VERSION 5.7 ;
  NOWIREEXTENSIONATPIN ON ;
  DIVIDERCHAR "/" ;
  BUSBITCHARS "[]" ;
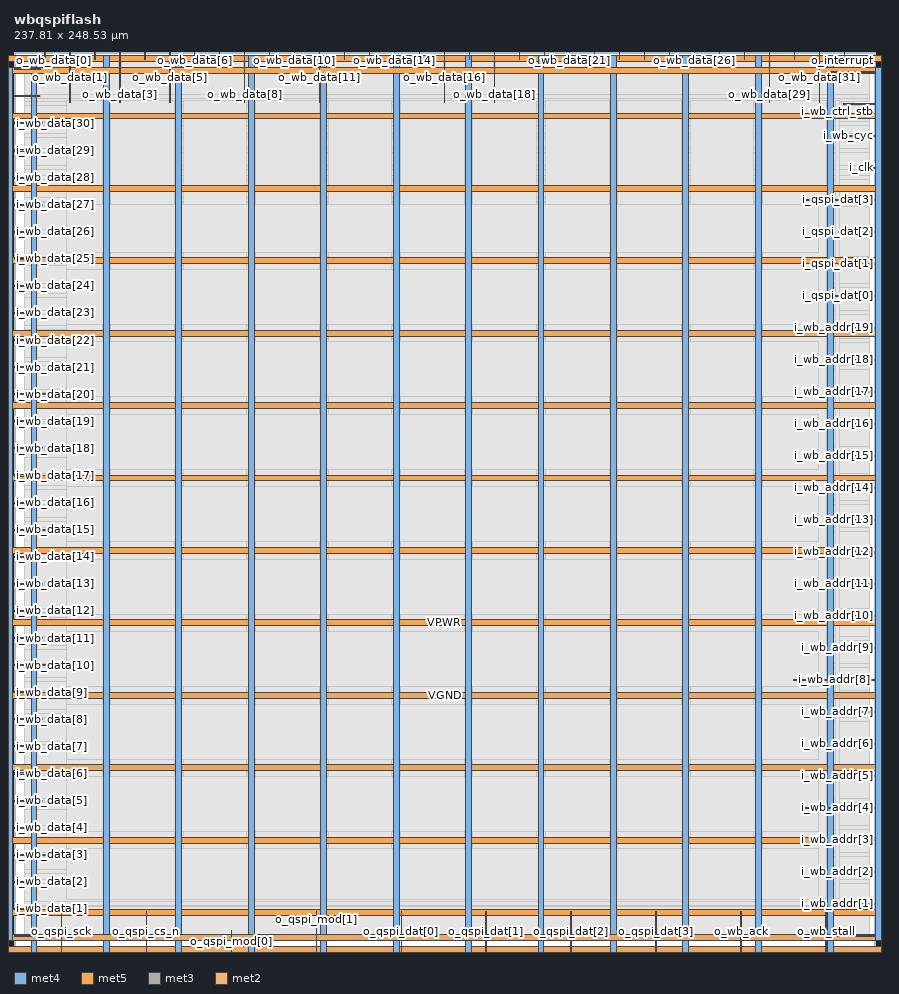
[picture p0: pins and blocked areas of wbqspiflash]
MACRO wbqspiflash
  CLASS BLOCK ;
  FOREIGN wbqspiflash ;
  ORIGIN 0.000 0.000 ;
  SIZE 237.810 BY 248.530 ;
  PIN VGND
    DIRECTION INOUT ;
    USE GROUND ;
    PORT
      LAYER met4 ;
        RECT -5.380 -0.020 -3.780 247.540 ;
    END
    PORT
      LAYER met5 ;
        RECT -5.380 -0.020 242.740 1.580 ;
    END
    PORT
      LAYER met5 ;
        RECT -5.380 245.940 242.740 247.540 ;
    END
    PORT
      LAYER met4 ;
        RECT 241.140 -0.020 242.740 247.540 ;
    END
    PORT
      LAYER met4 ;
        RECT 24.720 -0.020 26.320 247.540 ;
    END
    PORT
      LAYER met4 ;
        RECT 64.720 -0.020 66.320 247.540 ;
    END
    PORT
      LAYER met4 ;
        RECT 104.720 -0.020 106.320 247.540 ;
    END
    PORT
      LAYER met4 ;
        RECT 144.720 -0.020 146.320 247.540 ;
    END
    PORT
      LAYER met4 ;
        RECT 184.720 -0.020 186.320 247.540 ;
    END
    PORT
      LAYER met4 ;
        RECT 224.720 -0.020 226.320 247.540 ;
    END
    PORT
      LAYER met5 ;
        RECT -5.380 30.080 242.740 31.680 ;
    END
    PORT
      LAYER met5 ;
        RECT -5.380 70.080 242.740 71.680 ;
    END
    PORT
      LAYER met5 ;
        RECT -5.380 110.080 242.740 111.680 ;
    END
    PORT
      LAYER met5 ;
        RECT -5.380 150.080 242.740 151.680 ;
    END
    PORT
      LAYER met5 ;
        RECT -5.380 190.080 242.740 191.680 ;
    END
    PORT
      LAYER met5 ;
        RECT -5.380 230.080 242.740 231.680 ;
    END
  END VGND
  PIN VPWR
    DIRECTION INOUT ;
    USE POWER ;
    PORT
      LAYER met4 ;
        RECT -2.080 3.280 -0.480 244.240 ;
    END
    PORT
      LAYER met5 ;
        RECT -2.080 3.280 239.440 4.880 ;
    END
    PORT
      LAYER met5 ;
        RECT -2.080 242.640 239.440 244.240 ;
    END
    PORT
      LAYER met4 ;
        RECT 237.840 3.280 239.440 244.240 ;
    END
    PORT
      LAYER met4 ;
        RECT 4.720 -0.020 6.320 247.540 ;
    END
    PORT
      LAYER met4 ;
        RECT 44.720 -0.020 46.320 247.540 ;
    END
    PORT
      LAYER met4 ;
        RECT 84.720 -0.020 86.320 247.540 ;
    END
    PORT
      LAYER met4 ;
        RECT 124.720 -0.020 126.320 247.540 ;
    END
    PORT
      LAYER met4 ;
        RECT 164.720 -0.020 166.320 247.540 ;
    END
    PORT
      LAYER met4 ;
        RECT 204.720 -0.020 206.320 247.540 ;
    END
    PORT
      LAYER met5 ;
        RECT -5.380 10.080 242.740 11.680 ;
    END
    PORT
      LAYER met5 ;
        RECT -5.380 50.080 242.740 51.680 ;
    END
    PORT
      LAYER met5 ;
        RECT -5.380 90.080 242.740 91.680 ;
    END
    PORT
      LAYER met5 ;
        RECT -5.380 130.080 242.740 131.680 ;
    END
    PORT
      LAYER met5 ;
        RECT -5.380 170.080 242.740 171.680 ;
    END
    PORT
      LAYER met5 ;
        RECT -5.380 210.080 242.740 211.680 ;
    END
  END VPWR
  PIN i_clk
    DIRECTION INPUT ;
    USE SIGNAL ;
    PORT
      LAYER met3 ;
        RECT 234.910 216.430 237.810 216.730 ;
    END
  END i_clk
  PIN i_qspi_dat[0]
    DIRECTION INPUT ;
    USE SIGNAL ;
    PORT
      LAYER met3 ;
        RECT 224.390 181.070 237.810 181.370 ;
    END
  END i_qspi_dat[0]
  PIN i_qspi_dat[1]
    DIRECTION INPUT ;
    USE SIGNAL ;
    PORT
      LAYER met3 ;
        RECT 227.545 189.910 237.810 190.210 ;
    END
  END i_qspi_dat[1]
  PIN i_qspi_dat[2]
    DIRECTION INPUT ;
    USE SIGNAL ;
    PORT
      LAYER met3 ;
        RECT 227.545 198.750 237.810 199.050 ;
    END
  END i_qspi_dat[2]
  PIN i_qspi_dat[3]
    DIRECTION INPUT ;
    USE SIGNAL ;
    PORT
      LAYER met3 ;
        RECT 218.410 207.590 237.810 207.890 ;
    END
  END i_qspi_dat[3]
  PIN i_wb_addr[0]
    DIRECTION INPUT ;
    USE SIGNAL ;
    PORT
      LAYER met3 ;
        RECT 227.150 4.270 237.810 4.570 ;
    END
  END i_wb_addr[0]
  PIN i_wb_addr[10]
    DIRECTION INPUT ;
    USE SIGNAL ;
    PORT
      LAYER met3 ;
        RECT 224.390 92.670 237.810 92.970 ;
    END
  END i_wb_addr[10]
  PIN i_wb_addr[11]
    DIRECTION INPUT ;
    USE SIGNAL ;
    PORT
      LAYER met3 ;
        RECT 227.610 101.510 237.810 101.810 ;
    END
  END i_wb_addr[11]
  PIN i_wb_addr[12]
    DIRECTION INPUT ;
    USE SIGNAL ;
    PORT
      LAYER met3 ;
        RECT 227.150 110.350 237.810 110.650 ;
    END
  END i_wb_addr[12]
  PIN i_wb_addr[13]
    DIRECTION INPUT ;
    USE SIGNAL ;
    PORT
      LAYER met3 ;
        RECT 227.610 119.190 237.810 119.490 ;
    END
  END i_wb_addr[13]
  PIN i_wb_addr[14]
    DIRECTION INPUT ;
    USE SIGNAL ;
    PORT
      LAYER met3 ;
        RECT 227.610 128.030 237.810 128.330 ;
    END
  END i_wb_addr[14]
  PIN i_wb_addr[15]
    DIRECTION INPUT ;
    USE SIGNAL ;
    PORT
      LAYER met3 ;
        RECT 227.610 136.870 237.810 137.170 ;
    END
  END i_wb_addr[15]
  PIN i_wb_addr[16]
    DIRECTION INPUT ;
    USE SIGNAL ;
    PORT
      LAYER met3 ;
        RECT 224.390 145.710 237.810 146.010 ;
    END
  END i_wb_addr[16]
  PIN i_wb_addr[17]
    DIRECTION INPUT ;
    USE SIGNAL ;
    PORT
      LAYER met3 ;
        RECT 227.150 154.550 237.810 154.850 ;
    END
  END i_wb_addr[17]
  PIN i_wb_addr[18]
    DIRECTION INPUT ;
    USE SIGNAL ;
    PORT
      LAYER met3 ;
        RECT 227.610 163.390 237.810 163.690 ;
    END
  END i_wb_addr[18]
  PIN i_wb_addr[19]
    DIRECTION INPUT ;
    USE SIGNAL ;
    PORT
      LAYER met3 ;
        RECT 227.150 172.230 237.810 172.530 ;
    END
  END i_wb_addr[19]
  PIN i_wb_addr[1]
    DIRECTION INPUT ;
    USE SIGNAL ;
    PORT
      LAYER met3 ;
        RECT 231.750 13.110 237.810 13.410 ;
    END
  END i_wb_addr[1]
  PIN i_wb_addr[2]
    DIRECTION INPUT ;
    USE SIGNAL ;
    PORT
      LAYER met3 ;
        RECT 227.610 21.950 237.810 22.250 ;
    END
  END i_wb_addr[2]
  PIN i_wb_addr[3]
    DIRECTION INPUT ;
    USE SIGNAL ;
    PORT
      LAYER met3 ;
        RECT 227.610 30.790 237.810 31.090 ;
    END
  END i_wb_addr[3]
  PIN i_wb_addr[4]
    DIRECTION INPUT ;
    USE SIGNAL ;
    PORT
      LAYER met3 ;
        RECT 217.950 39.630 237.810 39.930 ;
    END
  END i_wb_addr[4]
  PIN i_wb_addr[5]
    DIRECTION INPUT ;
    USE SIGNAL ;
    PORT
      LAYER met3 ;
        RECT 227.610 48.470 237.810 48.770 ;
    END
  END i_wb_addr[5]
  PIN i_wb_addr[6]
    DIRECTION INPUT ;
    USE SIGNAL ;
    PORT
      LAYER met3 ;
        RECT 228.530 57.310 237.810 57.610 ;
    END
  END i_wb_addr[6]
  PIN i_wb_addr[7]
    DIRECTION INPUT ;
    USE SIGNAL ;
    PORT
      LAYER met3 ;
        RECT 231.750 66.150 237.810 66.450 ;
    END
  END i_wb_addr[7]
  PIN i_wb_addr[8]
    DIRECTION INPUT ;
    USE SIGNAL ;
    PORT
      LAYER met3 ;
        RECT 215.190 74.990 237.810 75.290 ;
    END
  END i_wb_addr[8]
  PIN i_wb_addr[9]
    DIRECTION INPUT ;
    USE SIGNAL ;
    PORT
      LAYER met3 ;
        RECT 228.070 83.830 237.810 84.130 ;
    END
  END i_wb_addr[9]
  PIN i_wb_ctrl_stb
    DIRECTION INPUT ;
    USE SIGNAL ;
    PORT
      LAYER met3 ;
        RECT 228.990 234.110 237.810 234.410 ;
    END
  END i_wb_ctrl_stb
  PIN i_wb_cyc
    DIRECTION INPUT ;
    USE SIGNAL ;
    PORT
      LAYER met3 ;
        RECT 228.530 225.270 237.810 225.570 ;
    END
  END i_wb_cyc
  PIN i_wb_data[0]
    DIRECTION INPUT ;
    USE SIGNAL ;
    PORT
      LAYER met3 ;
        RECT 0.000 4.270 7.910 4.570 ;
    END
  END i_wb_data[0]
  PIN i_wb_data[10]
    DIRECTION INPUT ;
    USE SIGNAL ;
    PORT
      LAYER met3 ;
        RECT 0.000 79.070 15.730 79.370 ;
    END
  END i_wb_data[10]
  PIN i_wb_data[11]
    DIRECTION INPUT ;
    USE SIGNAL ;
    PORT
      LAYER met3 ;
        RECT 0.000 86.550 7.910 86.850 ;
    END
  END i_wb_data[11]
  PIN i_wb_data[12]
    DIRECTION INPUT ;
    USE SIGNAL ;
    PORT
      LAYER met3 ;
        RECT 0.000 94.030 4.230 94.330 ;
    END
  END i_wb_data[12]
  PIN i_wb_data[13]
    DIRECTION INPUT ;
    USE SIGNAL ;
    PORT
      LAYER met3 ;
        RECT 0.000 101.510 7.910 101.810 ;
    END
  END i_wb_data[13]
  PIN i_wb_data[14]
    DIRECTION INPUT ;
    USE SIGNAL ;
    PORT
      LAYER met3 ;
        RECT 0.000 108.990 4.230 109.290 ;
    END
  END i_wb_data[14]
  PIN i_wb_data[15]
    DIRECTION INPUT ;
    USE SIGNAL ;
    PORT
      LAYER met3 ;
        RECT 0.000 116.470 15.730 116.770 ;
    END
  END i_wb_data[15]
  PIN i_wb_data[16]
    DIRECTION INPUT ;
    USE SIGNAL ;
    PORT
      LAYER met3 ;
        RECT 0.000 123.950 3.770 124.250 ;
    END
  END i_wb_data[16]
  PIN i_wb_data[17]
    DIRECTION INPUT ;
    USE SIGNAL ;
    PORT
      LAYER met3 ;
        RECT 0.000 131.430 3.770 131.730 ;
    END
  END i_wb_data[17]
  PIN i_wb_data[18]
    DIRECTION INPUT ;
    USE SIGNAL ;
    PORT
      LAYER met3 ;
        RECT 0.000 138.910 7.910 139.210 ;
    END
  END i_wb_data[18]
  PIN i_wb_data[19]
    DIRECTION INPUT ;
    USE SIGNAL ;
    PORT
      LAYER met3 ;
        RECT 0.000 146.390 2.850 146.690 ;
    END
  END i_wb_data[19]
  PIN i_wb_data[1]
    DIRECTION INPUT ;
    USE SIGNAL ;
    PORT
      LAYER met3 ;
        RECT 0.000 11.750 3.770 12.050 ;
    END
  END i_wb_data[1]
  PIN i_wb_data[20]
    DIRECTION INPUT ;
    USE SIGNAL ;
    PORT
      LAYER met3 ;
        RECT 0.000 153.870 18.950 154.170 ;
    END
  END i_wb_data[20]
  PIN i_wb_data[21]
    DIRECTION INPUT ;
    USE SIGNAL ;
    PORT
      LAYER met3 ;
        RECT 0.000 161.350 4.230 161.650 ;
    END
  END i_wb_data[21]
  PIN i_wb_data[22]
    DIRECTION INPUT ;
    USE SIGNAL ;
    PORT
      LAYER met3 ;
        RECT 0.000 168.830 3.770 169.130 ;
    END
  END i_wb_data[22]
  PIN i_wb_data[23]
    DIRECTION INPUT ;
    USE SIGNAL ;
    PORT
      LAYER met3 ;
        RECT 0.000 176.310 4.230 176.610 ;
    END
  END i_wb_data[23]
  PIN i_wb_data[24]
    DIRECTION INPUT ;
    USE SIGNAL ;
    PORT
      LAYER met3 ;
        RECT 0.000 183.790 2.850 184.090 ;
    END
  END i_wb_data[24]
  PIN i_wb_data[25]
    DIRECTION INPUT ;
    USE SIGNAL ;
    PORT
      LAYER met3 ;
        RECT 0.000 191.270 4.230 191.570 ;
    END
  END i_wb_data[25]
  PIN i_wb_data[26]
    DIRECTION INPUT ;
    USE SIGNAL ;
    PORT
      LAYER met3 ;
        RECT 0.000 198.750 4.230 199.050 ;
    END
  END i_wb_data[26]
  PIN i_wb_data[27]
    DIRECTION INPUT ;
    USE SIGNAL ;
    PORT
      LAYER met3 ;
        RECT 0.000 206.230 7.910 206.530 ;
    END
  END i_wb_data[27]
  PIN i_wb_data[28]
    DIRECTION INPUT ;
    USE SIGNAL ;
    PORT
      LAYER met3 ;
        RECT 0.000 213.710 6.990 214.010 ;
    END
  END i_wb_data[28]
  PIN i_wb_data[29]
    DIRECTION INPUT ;
    USE SIGNAL ;
    PORT
      LAYER met3 ;
        RECT 0.000 221.190 3.770 221.490 ;
    END
  END i_wb_data[29]
  PIN i_wb_data[2]
    DIRECTION INPUT ;
    USE SIGNAL ;
    PORT
      LAYER met3 ;
        RECT 0.000 19.230 4.230 19.530 ;
    END
  END i_wb_data[2]
  PIN i_wb_data[30]
    DIRECTION INPUT ;
    USE SIGNAL ;
    PORT
      LAYER met3 ;
        RECT 0.000 228.670 7.910 228.970 ;
    END
  END i_wb_data[30]
  PIN i_wb_data[31]
    DIRECTION INPUT ;
    USE SIGNAL ;
    PORT
      LAYER met3 ;
        RECT 0.000 236.150 6.990 236.450 ;
    END
  END i_wb_data[31]
  PIN i_wb_data[3]
    DIRECTION INPUT ;
    USE SIGNAL ;
    PORT
      LAYER met3 ;
        RECT 0.000 26.710 11.130 27.010 ;
    END
  END i_wb_data[3]
  PIN i_wb_data[4]
    DIRECTION INPUT ;
    USE SIGNAL ;
    PORT
      LAYER met3 ;
        RECT 0.000 34.190 4.230 34.490 ;
    END
  END i_wb_data[4]
  PIN i_wb_data[5]
    DIRECTION INPUT ;
    USE SIGNAL ;
    PORT
      LAYER met3 ;
        RECT 0.000 41.670 7.910 41.970 ;
    END
  END i_wb_data[5]
  PIN i_wb_data[6]
    DIRECTION INPUT ;
    USE SIGNAL ;
    PORT
      LAYER met3 ;
        RECT 0.000 49.150 3.770 49.450 ;
    END
  END i_wb_data[6]
  PIN i_wb_data[7]
    DIRECTION INPUT ;
    USE SIGNAL ;
    PORT
      LAYER met3 ;
        RECT 0.000 56.630 4.230 56.930 ;
    END
  END i_wb_data[7]
  PIN i_wb_data[8]
    DIRECTION INPUT ;
    USE SIGNAL ;
    PORT
      LAYER met3 ;
        RECT 0.000 64.110 7.910 64.410 ;
    END
  END i_wb_data[8]
  PIN i_wb_data[9]
    DIRECTION INPUT ;
    USE SIGNAL ;
    PORT
      LAYER met3 ;
        RECT 0.000 71.590 3.770 71.890 ;
    END
  END i_wb_data[9]
  PIN i_wb_data_stb
    DIRECTION INPUT ;
    USE SIGNAL ;
    PORT
      LAYER met3 ;
        RECT 0.000 243.630 7.450 243.930 ;
    END
  END i_wb_data_stb
  PIN i_wb_we
    DIRECTION INPUT ;
    USE SIGNAL ;
    PORT
      LAYER met3 ;
        RECT 224.390 242.950 237.810 243.250 ;
    END
  END i_wb_we
  PIN o_interrupt
    DIRECTION OUTPUT TRISTATE ;
    USE SIGNAL ;
    PORT
      LAYER met2 ;
        RECT 229.240 246.530 229.380 248.530 ;
    END
  END o_interrupt
  PIN o_qspi_cs_n
    DIRECTION OUTPUT TRISTATE ;
    USE SIGNAL ;
    PORT
      LAYER met2 ;
        RECT 36.500 0.000 36.640 11.260 ;
    END
  END o_qspi_cs_n
  PIN o_qspi_dat[0]
    DIRECTION OUTPUT TRISTATE ;
    USE SIGNAL ;
    PORT
      LAYER met2 ;
        RECT 106.880 0.000 107.020 11.260 ;
    END
  END o_qspi_dat[0]
  PIN o_qspi_dat[1]
    DIRECTION OUTPUT TRISTATE ;
    USE SIGNAL ;
    PORT
      LAYER met2 ;
        RECT 130.340 0.000 130.480 11.260 ;
    END
  END o_qspi_dat[1]
  PIN o_qspi_dat[2]
    DIRECTION OUTPUT TRISTATE ;
    USE SIGNAL ;
    PORT
      LAYER met2 ;
        RECT 153.800 0.000 153.940 11.260 ;
    END
  END o_qspi_dat[2]
  PIN o_qspi_dat[3]
    DIRECTION OUTPUT TRISTATE ;
    USE SIGNAL ;
    PORT
      LAYER met2 ;
        RECT 177.260 0.000 177.400 11.260 ;
    END
  END o_qspi_dat[3]
  PIN o_qspi_mod[0]
    DIRECTION OUTPUT TRISTATE ;
    USE SIGNAL ;
    PORT
      LAYER met2 ;
        RECT 59.960 0.000 60.100 5.820 ;
    END
  END o_qspi_mod[0]
  PIN o_qspi_mod[1]
    DIRECTION OUTPUT TRISTATE ;
    USE SIGNAL ;
    PORT
      LAYER met2 ;
        RECT 83.420 0.000 83.560 11.260 ;
    END
  END o_qspi_mod[1]
  PIN o_qspi_sck
    DIRECTION OUTPUT TRISTATE ;
    USE SIGNAL ;
    PORT
      LAYER met2 ;
        RECT 13.040 0.000 13.180 11.260 ;
    END
  END o_qspi_sck
  PIN o_wb_ack
    DIRECTION OUTPUT TRISTATE ;
    USE SIGNAL ;
    PORT
      LAYER met2 ;
        RECT 200.720 0.000 200.860 11.260 ;
    END
  END o_wb_ack
  PIN o_wb_data[0]
    DIRECTION OUTPUT TRISTATE ;
    USE SIGNAL ;
    PORT
      LAYER met2 ;
        RECT 8.440 246.530 8.580 248.530 ;
    END
  END o_wb_data[0]
  PIN o_wb_data[10]
    DIRECTION OUTPUT TRISTATE ;
    USE SIGNAL ;
    PORT
      LAYER met2 ;
        RECT 77.440 246.530 77.580 248.530 ;
    END
  END o_wb_data[10]
  PIN o_wb_data[11]
    DIRECTION OUTPUT TRISTATE ;
    USE SIGNAL ;
    PORT
      LAYER met2 ;
        RECT 84.340 234.560 84.480 248.530 ;
    END
  END o_wb_data[11]
  PIN o_wb_data[12]
    DIRECTION OUTPUT TRISTATE ;
    USE SIGNAL ;
    PORT
      LAYER met2 ;
        RECT 91.240 246.530 91.380 248.530 ;
    END
  END o_wb_data[12]
  PIN o_wb_data[13]
    DIRECTION OUTPUT TRISTATE ;
    USE SIGNAL ;
    PORT
      LAYER met2 ;
        RECT 98.140 246.530 98.280 248.530 ;
    END
  END o_wb_data[13]
  PIN o_wb_data[14]
    DIRECTION OUTPUT TRISTATE ;
    USE SIGNAL ;
    PORT
      LAYER met2 ;
        RECT 105.040 246.530 105.180 248.530 ;
    END
  END o_wb_data[14]
  PIN o_wb_data[15]
    DIRECTION OUTPUT TRISTATE ;
    USE SIGNAL ;
    PORT
      LAYER met2 ;
        RECT 111.940 246.530 112.080 248.530 ;
    END
  END o_wb_data[15]
  PIN o_wb_data[16]
    DIRECTION OUTPUT TRISTATE ;
    USE SIGNAL ;
    PORT
      LAYER met2 ;
        RECT 118.840 234.560 118.980 248.530 ;
    END
  END o_wb_data[16]
  PIN o_wb_data[17]
    DIRECTION OUTPUT TRISTATE ;
    USE SIGNAL ;
    PORT
      LAYER met2 ;
        RECT 125.740 246.530 125.880 248.530 ;
    END
  END o_wb_data[17]
  PIN o_wb_data[18]
    DIRECTION OUTPUT TRISTATE ;
    USE SIGNAL ;
    PORT
      LAYER met2 ;
        RECT 132.640 234.560 132.780 248.530 ;
    END
  END o_wb_data[18]
  PIN o_wb_data[19]
    DIRECTION OUTPUT TRISTATE ;
    USE SIGNAL ;
    PORT
      LAYER met2 ;
        RECT 139.540 246.530 139.680 248.530 ;
    END
  END o_wb_data[19]
  PIN o_wb_data[1]
    DIRECTION OUTPUT TRISTATE ;
    USE SIGNAL ;
    PORT
      LAYER met2 ;
        RECT 15.340 234.560 15.480 248.530 ;
    END
  END o_wb_data[1]
  PIN o_wb_data[20]
    DIRECTION OUTPUT TRISTATE ;
    USE SIGNAL ;
    PORT
      LAYER met2 ;
        RECT 146.440 246.530 146.580 248.530 ;
    END
  END o_wb_data[20]
  PIN o_wb_data[21]
    DIRECTION OUTPUT TRISTATE ;
    USE SIGNAL ;
    PORT
      LAYER met2 ;
        RECT 153.340 246.530 153.480 248.530 ;
    END
  END o_wb_data[21]
  PIN o_wb_data[22]
    DIRECTION OUTPUT TRISTATE ;
    USE SIGNAL ;
    PORT
      LAYER met2 ;
        RECT 160.240 246.530 160.380 248.530 ;
    END
  END o_wb_data[22]
  PIN o_wb_data[23]
    DIRECTION OUTPUT TRISTATE ;
    USE SIGNAL ;
    PORT
      LAYER met2 ;
        RECT 167.140 246.530 167.280 248.530 ;
    END
  END o_wb_data[23]
  PIN o_wb_data[24]
    DIRECTION OUTPUT TRISTATE ;
    USE SIGNAL ;
    PORT
      LAYER met2 ;
        RECT 174.040 246.530 174.180 248.530 ;
    END
  END o_wb_data[24]
  PIN o_wb_data[25]
    DIRECTION OUTPUT TRISTATE ;
    USE SIGNAL ;
    PORT
      LAYER met2 ;
        RECT 180.940 246.530 181.080 248.530 ;
    END
  END o_wb_data[25]
  PIN o_wb_data[26]
    DIRECTION OUTPUT TRISTATE ;
    USE SIGNAL ;
    PORT
      LAYER met2 ;
        RECT 187.840 246.530 187.980 248.530 ;
    END
  END o_wb_data[26]
  PIN o_wb_data[27]
    DIRECTION OUTPUT TRISTATE ;
    USE SIGNAL ;
    PORT
      LAYER met2 ;
        RECT 194.740 246.530 194.880 248.530 ;
    END
  END o_wb_data[27]
  PIN o_wb_data[28]
    DIRECTION OUTPUT TRISTATE ;
    USE SIGNAL ;
    PORT
      LAYER met2 ;
        RECT 201.640 246.530 201.780 248.530 ;
    END
  END o_wb_data[28]
  PIN o_wb_data[29]
    DIRECTION OUTPUT TRISTATE ;
    USE SIGNAL ;
    PORT
      LAYER met2 ;
        RECT 208.540 234.560 208.680 248.530 ;
    END
  END o_wb_data[29]
  PIN o_wb_data[2]
    DIRECTION OUTPUT TRISTATE ;
    USE SIGNAL ;
    PORT
      LAYER met2 ;
        RECT 22.240 246.530 22.380 248.530 ;
    END
  END o_wb_data[2]
  PIN o_wb_data[30]
    DIRECTION OUTPUT TRISTATE ;
    USE SIGNAL ;
    PORT
      LAYER met2 ;
        RECT 215.440 246.530 215.580 248.530 ;
    END
  END o_wb_data[30]
  PIN o_wb_data[31]
    DIRECTION OUTPUT TRISTATE ;
    USE SIGNAL ;
    PORT
      LAYER met2 ;
        RECT 222.340 234.560 222.480 248.530 ;
    END
  END o_wb_data[31]
  PIN o_wb_data[3]
    DIRECTION OUTPUT TRISTATE ;
    USE SIGNAL ;
    PORT
      LAYER met2 ;
        RECT 29.140 234.560 29.280 248.530 ;
    END
  END o_wb_data[3]
  PIN o_wb_data[4]
    DIRECTION OUTPUT TRISTATE ;
    USE SIGNAL ;
    PORT
      LAYER met2 ;
        RECT 36.040 246.530 36.180 248.530 ;
    END
  END o_wb_data[4]
  PIN o_wb_data[5]
    DIRECTION OUTPUT TRISTATE ;
    USE SIGNAL ;
    PORT
      LAYER met2 ;
        RECT 42.940 234.560 43.080 248.530 ;
    END
  END o_wb_data[5]
  PIN o_wb_data[6]
    DIRECTION OUTPUT TRISTATE ;
    USE SIGNAL ;
    PORT
      LAYER met2 ;
        RECT 49.840 246.530 49.980 248.530 ;
    END
  END o_wb_data[6]
  PIN o_wb_data[7]
    DIRECTION OUTPUT TRISTATE ;
    USE SIGNAL ;
    PORT
      LAYER met2 ;
        RECT 56.740 246.530 56.880 248.530 ;
    END
  END o_wb_data[7]
  PIN o_wb_data[8]
    DIRECTION OUTPUT TRISTATE ;
    USE SIGNAL ;
    PORT
      LAYER met2 ;
        RECT 63.640 234.560 63.780 248.530 ;
    END
  END o_wb_data[8]
  PIN o_wb_data[9]
    DIRECTION OUTPUT TRISTATE ;
    USE SIGNAL ;
    PORT
      LAYER met2 ;
        RECT 70.540 246.530 70.680 248.530 ;
    END
  END o_wb_data[9]
  PIN o_wb_stall
    DIRECTION OUTPUT TRISTATE ;
    USE SIGNAL ;
    PORT
      LAYER met2 ;
        RECT 224.180 0.000 224.320 11.260 ;
    END
  END o_wb_stall
  OBS
      LAYER li1 ;
        RECT 5.520 10.795 231.840 236.725 ;
      LAYER met1 ;
        RECT 2.830 5.820 231.840 236.880 ;
      LAYER met2 ;
        RECT 2.850 246.250 8.160 247.250 ;
        RECT 8.860 246.250 15.060 247.250 ;
        RECT 2.850 234.280 15.060 246.250 ;
        RECT 15.760 246.250 21.960 247.250 ;
        RECT 22.660 246.250 28.860 247.250 ;
        RECT 15.760 234.280 28.860 246.250 ;
        RECT 29.560 246.250 35.760 247.250 ;
        RECT 36.460 246.250 42.660 247.250 ;
        RECT 29.560 234.280 42.660 246.250 ;
        RECT 43.360 246.250 49.560 247.250 ;
        RECT 50.260 246.250 56.460 247.250 ;
        RECT 57.160 246.250 63.360 247.250 ;
        RECT 43.360 234.280 63.360 246.250 ;
        RECT 64.060 246.250 70.260 247.250 ;
        RECT 70.960 246.250 77.160 247.250 ;
        RECT 77.860 246.250 84.060 247.250 ;
        RECT 64.060 234.280 84.060 246.250 ;
        RECT 84.760 246.250 90.960 247.250 ;
        RECT 91.660 246.250 97.860 247.250 ;
        RECT 98.560 246.250 104.760 247.250 ;
        RECT 105.460 246.250 111.660 247.250 ;
        RECT 112.360 246.250 118.560 247.250 ;
        RECT 84.760 234.280 118.560 246.250 ;
        RECT 119.260 246.250 125.460 247.250 ;
        RECT 126.160 246.250 132.360 247.250 ;
        RECT 119.260 234.280 132.360 246.250 ;
        RECT 133.060 246.250 139.260 247.250 ;
        RECT 139.960 246.250 146.160 247.250 ;
        RECT 146.860 246.250 153.060 247.250 ;
        RECT 153.760 246.250 159.960 247.250 ;
        RECT 160.660 246.250 166.860 247.250 ;
        RECT 167.560 246.250 173.760 247.250 ;
        RECT 174.460 246.250 180.660 247.250 ;
        RECT 181.360 246.250 187.560 247.250 ;
        RECT 188.260 246.250 194.460 247.250 ;
        RECT 195.160 246.250 201.360 247.250 ;
        RECT 202.060 246.250 208.260 247.250 ;
        RECT 133.060 234.280 208.260 246.250 ;
        RECT 208.960 246.250 215.160 247.250 ;
        RECT 215.860 246.250 222.060 247.250 ;
        RECT 208.960 234.280 222.060 246.250 ;
        RECT 222.760 246.250 228.960 247.250 ;
        RECT 229.660 246.250 231.750 247.250 ;
        RECT 222.760 234.280 231.750 246.250 ;
        RECT 2.850 11.540 231.750 234.280 ;
        RECT 2.850 4.235 12.760 11.540 ;
        RECT 13.460 4.235 36.220 11.540 ;
        RECT 36.920 6.100 83.140 11.540 ;
        RECT 36.920 4.235 59.680 6.100 ;
        RECT 60.380 4.235 83.140 6.100 ;
        RECT 83.840 4.235 106.600 11.540 ;
        RECT 107.300 4.235 130.060 11.540 ;
        RECT 130.760 4.235 153.520 11.540 ;
        RECT 154.220 4.235 176.980 11.540 ;
        RECT 177.680 4.235 200.440 11.540 ;
        RECT 201.140 4.235 223.900 11.540 ;
        RECT 224.600 4.235 231.750 11.540 ;
      LAYER met3 ;
        RECT 7.850 243.650 236.130 243.945 ;
        RECT 7.850 243.230 223.990 243.650 ;
        RECT 2.825 242.550 223.990 243.230 ;
        RECT 2.825 236.850 236.130 242.550 ;
        RECT 7.390 235.750 236.130 236.850 ;
        RECT 2.825 234.810 236.130 235.750 ;
        RECT 2.825 233.710 228.590 234.810 ;
        RECT 2.825 229.370 236.130 233.710 ;
        RECT 8.310 228.270 236.130 229.370 ;
        RECT 2.825 225.970 236.130 228.270 ;
        RECT 2.825 224.870 228.130 225.970 ;
        RECT 2.825 221.890 236.130 224.870 ;
        RECT 4.170 220.790 236.130 221.890 ;
        RECT 2.825 217.130 236.130 220.790 ;
        RECT 2.825 216.030 234.510 217.130 ;
        RECT 2.825 214.410 236.130 216.030 ;
        RECT 7.390 213.310 236.130 214.410 ;
        RECT 2.825 208.290 236.130 213.310 ;
        RECT 2.825 207.190 218.010 208.290 ;
        RECT 2.825 206.930 236.130 207.190 ;
        RECT 8.310 205.830 236.130 206.930 ;
        RECT 2.825 199.450 236.130 205.830 ;
        RECT 4.630 198.350 227.145 199.450 ;
        RECT 2.825 191.970 236.130 198.350 ;
        RECT 4.630 190.870 236.130 191.970 ;
        RECT 2.825 190.610 236.130 190.870 ;
        RECT 2.825 189.510 227.145 190.610 ;
        RECT 2.825 184.490 236.130 189.510 ;
        RECT 3.250 183.390 236.130 184.490 ;
        RECT 2.825 181.770 236.130 183.390 ;
        RECT 2.825 180.670 223.990 181.770 ;
        RECT 2.825 177.010 236.130 180.670 ;
        RECT 4.630 175.910 236.130 177.010 ;
        RECT 2.825 172.930 236.130 175.910 ;
        RECT 2.825 171.830 226.750 172.930 ;
        RECT 2.825 169.530 236.130 171.830 ;
        RECT 4.170 168.430 236.130 169.530 ;
        RECT 2.825 164.090 236.130 168.430 ;
        RECT 2.825 162.990 227.210 164.090 ;
        RECT 2.825 162.050 236.130 162.990 ;
        RECT 4.630 160.950 236.130 162.050 ;
        RECT 2.825 155.250 236.130 160.950 ;
        RECT 2.825 154.570 226.750 155.250 ;
        RECT 19.350 154.150 226.750 154.570 ;
        RECT 19.350 153.470 236.130 154.150 ;
        RECT 2.825 147.090 236.130 153.470 ;
        RECT 3.250 146.410 236.130 147.090 ;
        RECT 3.250 145.990 223.990 146.410 ;
        RECT 2.825 145.310 223.990 145.990 ;
        RECT 2.825 139.610 236.130 145.310 ;
        RECT 8.310 138.510 236.130 139.610 ;
        RECT 2.825 137.570 236.130 138.510 ;
        RECT 2.825 136.470 227.210 137.570 ;
        RECT 2.825 132.130 236.130 136.470 ;
        RECT 4.170 131.030 236.130 132.130 ;
        RECT 2.825 128.730 236.130 131.030 ;
        RECT 2.825 127.630 227.210 128.730 ;
        RECT 2.825 124.650 236.130 127.630 ;
        RECT 4.170 123.550 236.130 124.650 ;
        RECT 2.825 119.890 236.130 123.550 ;
        RECT 2.825 118.790 227.210 119.890 ;
        RECT 2.825 117.170 236.130 118.790 ;
        RECT 16.130 116.070 236.130 117.170 ;
        RECT 2.825 111.050 236.130 116.070 ;
        RECT 2.825 109.950 226.750 111.050 ;
        RECT 2.825 109.690 236.130 109.950 ;
        RECT 4.630 108.590 236.130 109.690 ;
        RECT 2.825 102.210 236.130 108.590 ;
        RECT 8.310 101.110 227.210 102.210 ;
        RECT 2.825 94.730 236.130 101.110 ;
        RECT 4.630 93.630 236.130 94.730 ;
        RECT 2.825 93.370 236.130 93.630 ;
        RECT 2.825 92.270 223.990 93.370 ;
        RECT 2.825 87.250 236.130 92.270 ;
        RECT 8.310 86.150 236.130 87.250 ;
        RECT 2.825 84.530 236.130 86.150 ;
        RECT 2.825 83.430 227.670 84.530 ;
        RECT 2.825 79.770 236.130 83.430 ;
        RECT 16.130 78.670 236.130 79.770 ;
        RECT 2.825 75.690 236.130 78.670 ;
        RECT 2.825 74.590 214.790 75.690 ;
        RECT 2.825 72.290 236.130 74.590 ;
        RECT 4.170 71.190 236.130 72.290 ;
        RECT 2.825 66.850 236.130 71.190 ;
        RECT 2.825 65.750 231.350 66.850 ;
        RECT 2.825 64.810 236.130 65.750 ;
        RECT 8.310 63.710 236.130 64.810 ;
        RECT 2.825 58.010 236.130 63.710 ;
        RECT 2.825 57.330 228.130 58.010 ;
        RECT 4.630 56.910 228.130 57.330 ;
        RECT 4.630 56.230 236.130 56.910 ;
        RECT 2.825 49.850 236.130 56.230 ;
        RECT 4.170 49.170 236.130 49.850 ;
        RECT 4.170 48.750 227.210 49.170 ;
        RECT 2.825 48.070 227.210 48.750 ;
        RECT 2.825 42.370 236.130 48.070 ;
        RECT 8.310 41.270 236.130 42.370 ;
        RECT 2.825 40.330 236.130 41.270 ;
        RECT 2.825 39.230 217.550 40.330 ;
        RECT 2.825 34.890 236.130 39.230 ;
        RECT 4.630 33.790 236.130 34.890 ;
        RECT 2.825 31.490 236.130 33.790 ;
        RECT 2.825 30.390 227.210 31.490 ;
        RECT 2.825 27.410 236.130 30.390 ;
        RECT 11.530 26.310 236.130 27.410 ;
        RECT 2.825 22.650 236.130 26.310 ;
        RECT 2.825 21.550 227.210 22.650 ;
        RECT 2.825 19.930 236.130 21.550 ;
        RECT 4.630 18.830 236.130 19.930 ;
        RECT 2.825 13.810 236.130 18.830 ;
        RECT 2.825 12.710 231.350 13.810 ;
        RECT 2.825 12.450 236.130 12.710 ;
        RECT 4.170 11.350 236.130 12.450 ;
        RECT 2.825 4.970 236.130 11.350 ;
        RECT 8.310 4.255 226.750 4.970 ;
      LAYER met4 ;
        RECT 14.590 14.710 24.320 235.105 ;
        RECT 26.720 14.710 44.320 235.105 ;
        RECT 46.720 14.710 64.320 235.105 ;
        RECT 66.720 14.710 84.320 235.105 ;
        RECT 86.720 14.710 104.320 235.105 ;
        RECT 106.720 14.710 124.320 235.105 ;
        RECT 126.720 14.710 144.320 235.105 ;
        RECT 146.720 14.710 164.320 235.105 ;
        RECT 166.720 14.710 184.320 235.105 ;
        RECT 186.720 14.710 204.320 235.105 ;
        RECT 206.720 14.710 224.320 235.105 ;
        RECT 226.720 14.710 227.865 235.105 ;
      LAYER met5 ;
        RECT 14.380 193.280 222.060 206.500 ;
        RECT 14.380 173.280 222.060 188.480 ;
        RECT 14.380 153.280 222.060 168.480 ;
        RECT 14.380 133.280 222.060 148.480 ;
        RECT 14.380 113.280 222.060 128.480 ;
        RECT 14.380 93.280 222.060 108.480 ;
        RECT 14.380 73.280 222.060 88.480 ;
        RECT 14.380 53.280 222.060 68.480 ;
        RECT 14.380 33.280 222.060 48.480 ;
        RECT 14.380 14.500 222.060 28.480 ;
  END
END wbqspiflash
END LIBRARY

